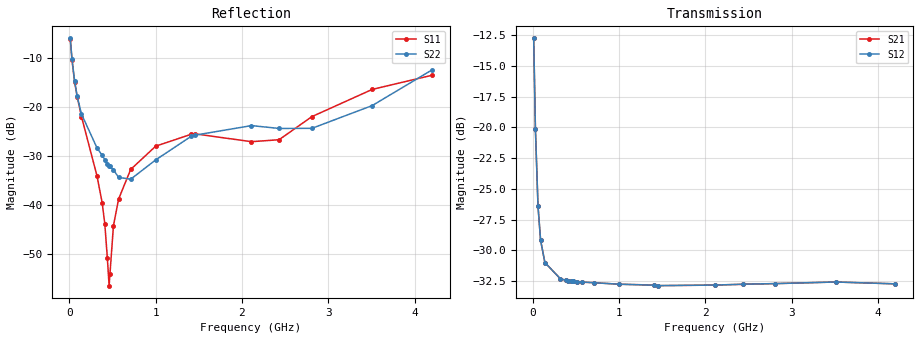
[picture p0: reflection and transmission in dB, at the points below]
! Integrated Device Technology
! Corporate Headquarters
! 6024 Silver Creek Valley Road
! San Jose, CA 95138  USA
! Phone:  1-408-284-8200
! Toll Free:  1-800-223-1366
! Webpage:  http://www.idt.com/
! Timing and RF Division
! 515 Groton Road, Suite 102
! Westford, MA 01886-6024
! Device:  F1950
! Description: 7-bit 0.25 dB Digital Step Attenuator
! Frequency:  150.0 -  4000.00 MHz
! Package:  4x4 mm Thin QFN Plastic Package: 24 pin
! Ports:  2 RF, 12 DC
!  Pin  1  = D0
!  Pin  2  = VDD
!  Pin  3  = Vmode
!  Pin  4  = GND
!  Pin  5  = RF1  =  Port 1
!  Pin  6  = GND
!  Pin  7  = GND
!  Pin  8  = GND
!  Pin  9  = GND
!  Pin 10  = GND
!  Pin 11  = GND
!  Pin 12  = GND
!  Pin 13  = GND
!  Pin 14  = RF2  =  Port 2
!  Pin 15  = GND
!  Pin 16  = LE
!  Pin 17  = CLK
!  Pin 18  = DATE
!  Pin 19  = D6
!  Pin 20  = D5
!  Pin 21  = D4
!  Pin 22  = D3
!  Pin 23  = D2
!  Pin 24  = D1
! State:  127
! Atten State:  31.75 dB
! Voltage:  +5.00 Volts
! Current:  Not Measured mA
! Data:  The device was measured on a the F195X evaluation board which has
!  individual transmission lines to the RF pins.  Data was collected
!  using a calibrated network analyzer.  The evaluation board was
!  de-embedded using a TRL calibration technique.
!  The reference plane is the edge of the package pin.
! Misc:  Board 2019
!  Action Tracker AT0250
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# GHz S dB R 50
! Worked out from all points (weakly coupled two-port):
!   420 points, 10 MHz to 4.2 GHz, reference 50 ohm
!   highest |S21| = -12.75 dB at 10 MHz (marker M1); lowest = -32.9 dB at 1.45 GHz (marker M2)
!   lowest |S11| = -56.4 dB at 460 MHz (marker M3), VSWR 1.00, Z = 49.9 - j0.0582 ohm
!   |S11| at or under -10 dB: 27.55 MHz to end of sweep
!   |S22| runs from -35.0 to -6.0 dB; largest |S21 - S12| = 7.6e-05
!   S11 on the Smith chart (normalised r, x): 10 MHz: 1.98, -1.23; 30 MHz: 1.27, -0.65; 60 MHz: 1.11, -0.37; 380 MHz: 1.01, -0.02; 4.2 GHz: 0.69, +0.17
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0.01  -6.23 -29.0  -12.75 -43.7  -12.75 -43.7  -6.03 -29.3
0.03  -10.48 -51.4  -20.12 -67.2  -20.12 -67.2  -10.26 -53.2
0.06  -14.92 -64.0  -26.41 -61.7  -26.40 -61.7  -14.62 -66.0
0.09  -17.95 -69.6  -29.17 -50.3  -29.17 -50.3  -17.85 -70.4
0.14  -21.98 -72.3  -30.99 -36.8  -30.99 -36.8  -21.46 -74.8
0.32  -34.08 -71.5  -32.31 -19.3  -32.31 -19.2  -28.37 -84.6
0.38  -39.59 -70.4  -32.42 -17.0  -32.42 -17.1  -29.87 -87.3
0.41  -43.80 -76.8  -32.46 -16.2  -32.45 -16.2  -30.76 -88.8
0.44  -50.87 -95.5  -32.49 -15.5  -32.48 -15.5  -31.58 -92.9
0.46  -56.44 -157.2  -32.50 -15.1  -32.50 -15.1  -31.99 -96.2
0.47  -54.03 164.8  -32.52 -14.9  -32.51 -14.9  -32.14 -97.9
0.51  -44.26 138.8  -32.54 -14.3  -32.54 -14.4  -32.83 -102.0
0.57  -38.78 133.9  -32.58 -13.7  -32.57 -13.6  -34.35 -112.8
0.71  -32.75 137.1  -32.63 -12.7  -32.63 -12.7  -34.74 -140.7
1  -28.00 147.0  -32.75 -12.3  -32.75 -12.3  -30.80 178.3
1.41  -25.59 161.9  -32.82 -12.8  -32.83 -12.8  -26.00 159.8
1.45  -25.48 162.0  -32.87 -12.8  -32.86 -12.8  -25.78 158.6
2.11  -27.09 156.0  -32.82 -15.4  -32.82 -15.5  -23.81 141.4
2.43  -26.69 124.1  -32.76 -16.3  -32.75 -16.4  -24.39 130.4
2.81  -21.98 104.1  -32.70 -18.6  -32.70 -18.6  -24.37 114.9
3.51  -16.43 116.5  -32.57 -22.2  -32.57 -22.2  -19.72 112.6
4.2  -13.56 145.1  -32.72 -23.0  -32.72 -23.1  -12.48 126.8
